VERSION 5.7 ;
BUSBITCHARS "[]" ;
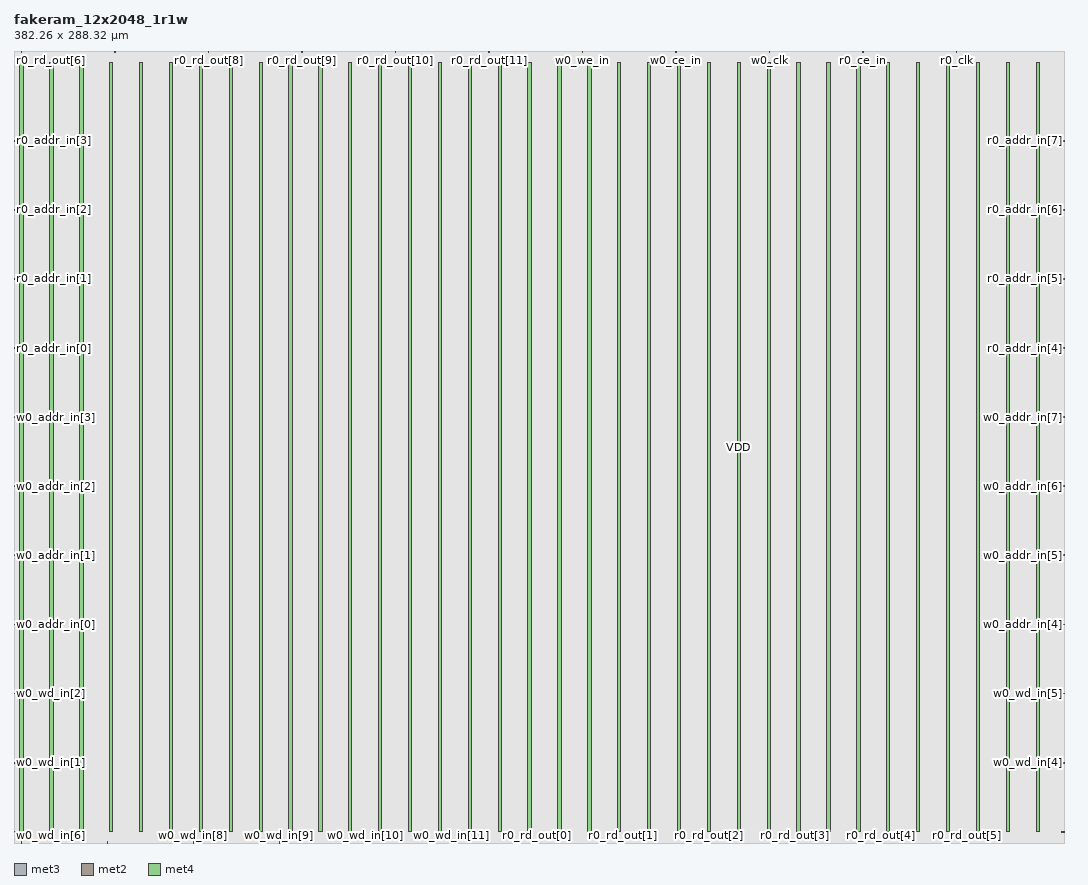
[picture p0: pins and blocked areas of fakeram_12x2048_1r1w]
MACRO fakeram_12x2048_1r1w
  FOREIGN fakeram_12x2048_1r1w 0 0 ;
  SYMMETRY X Y R90 ;
  SIZE 382.260 BY 288.320 ;
  CLASS BLOCK ;
  PIN w0_wd_in[0]
    DIRECTION INPUT ;
    USE SIGNAL ;
    SHAPE ABUTMENT ;
    PORT
      LAYER met3 ;
      RECT 0.000 3.930 0.900 4.230 ;
    END
  END w0_wd_in[0]
  PIN w0_wd_in[1]
    DIRECTION INPUT ;
    USE SIGNAL ;
    SHAPE ABUTMENT ;
    PORT
      LAYER met3 ;
      RECT 0.000 29.090 0.900 29.390 ;
    END
  END w0_wd_in[1]
  PIN w0_wd_in[2]
    DIRECTION INPUT ;
    USE SIGNAL ;
    SHAPE ABUTMENT ;
    PORT
      LAYER met3 ;
      RECT 0.000 54.250 0.900 54.550 ;
    END
  END w0_wd_in[2]
  PIN w0_wd_in[3]
    DIRECTION INPUT ;
    USE SIGNAL ;
    SHAPE ABUTMENT ;
    PORT
      LAYER met3 ;
      RECT 381.360 3.930 382.260 4.230 ;
    END
  END w0_wd_in[3]
  PIN w0_wd_in[4]
    DIRECTION INPUT ;
    USE SIGNAL ;
    SHAPE ABUTMENT ;
    PORT
      LAYER met3 ;
      RECT 381.360 29.090 382.260 29.390 ;
    END
  END w0_wd_in[4]
  PIN w0_wd_in[5]
    DIRECTION INPUT ;
    USE SIGNAL ;
    SHAPE ABUTMENT ;
    PORT
      LAYER met3 ;
      RECT 381.360 54.250 382.260 54.550 ;
    END
  END w0_wd_in[5]
  PIN w0_wd_in[6]
    DIRECTION OUTPUT ;
    USE SIGNAL ;
    SHAPE ABUTMENT ;
    PORT
      LAYER met2 ;
      RECT 2.690 0.000 2.830 0.420 ;
    END
  END w0_wd_in[6]
  PIN w0_wd_in[7]
    DIRECTION OUTPUT ;
    USE SIGNAL ;
    SHAPE ABUTMENT ;
    PORT
      LAYER met2 ;
      RECT 33.970 0.000 34.110 0.420 ;
    END
  END w0_wd_in[7]
  PIN w0_wd_in[8]
    DIRECTION OUTPUT ;
    USE SIGNAL ;
    SHAPE ABUTMENT ;
    PORT
      LAYER met2 ;
      RECT 65.250 0.000 65.390 0.420 ;
    END
  END w0_wd_in[8]
  PIN w0_wd_in[9]
    DIRECTION OUTPUT ;
    USE SIGNAL ;
    SHAPE ABUTMENT ;
    PORT
      LAYER met2 ;
      RECT 96.530 0.000 96.670 0.420 ;
    END
  END w0_wd_in[9]
  PIN w0_wd_in[10]
    DIRECTION OUTPUT ;
    USE SIGNAL ;
    SHAPE ABUTMENT ;
    PORT
      LAYER met2 ;
      RECT 127.810 0.000 127.950 0.420 ;
    END
  END w0_wd_in[10]
  PIN w0_wd_in[11]
    DIRECTION OUTPUT ;
    USE SIGNAL ;
    SHAPE ABUTMENT ;
    PORT
      LAYER met2 ;
      RECT 159.090 0.000 159.230 0.420 ;
    END
  END w0_wd_in[11]
  PIN r0_rd_out[0]
    DIRECTION OUTPUT ;
    USE SIGNAL ;
    SHAPE ABUTMENT ;
    PORT
      LAYER met2 ;
      RECT 190.370 0.000 190.510 0.420 ;
    END
  END r0_rd_out[0]
  PIN r0_rd_out[1]
    DIRECTION OUTPUT ;
    USE SIGNAL ;
    SHAPE ABUTMENT ;
    PORT
      LAYER met2 ;
      RECT 221.650 0.000 221.790 0.420 ;
    END
  END r0_rd_out[1]
  PIN r0_rd_out[2]
    DIRECTION OUTPUT ;
    USE SIGNAL ;
    SHAPE ABUTMENT ;
    PORT
      LAYER met2 ;
      RECT 252.930 0.000 253.070 0.420 ;
    END
  END r0_rd_out[2]
  PIN r0_rd_out[3]
    DIRECTION OUTPUT ;
    USE SIGNAL ;
    SHAPE ABUTMENT ;
    PORT
      LAYER met2 ;
      RECT 284.210 0.000 284.350 0.420 ;
    END
  END r0_rd_out[3]
  PIN r0_rd_out[4]
    DIRECTION OUTPUT ;
    USE SIGNAL ;
    SHAPE ABUTMENT ;
    PORT
      LAYER met2 ;
      RECT 315.490 0.000 315.630 0.420 ;
    END
  END r0_rd_out[4]
  PIN r0_rd_out[5]
    DIRECTION OUTPUT ;
    USE SIGNAL ;
    SHAPE ABUTMENT ;
    PORT
      LAYER met2 ;
      RECT 346.770 0.000 346.910 0.420 ;
    END
  END r0_rd_out[5]
  PIN r0_rd_out[6]
    DIRECTION OUTPUT ;
    USE SIGNAL ;
    SHAPE ABUTMENT ;
    PORT
      LAYER met2 ;
      RECT 2.690 287.900 2.830 288.320 ;
    END
  END r0_rd_out[6]
  PIN r0_rd_out[7]
    DIRECTION OUTPUT ;
    USE SIGNAL ;
    SHAPE ABUTMENT ;
    PORT
      LAYER met2 ;
      RECT 36.730 287.900 36.870 288.320 ;
    END
  END r0_rd_out[7]
  PIN r0_rd_out[8]
    DIRECTION OUTPUT ;
    USE SIGNAL ;
    SHAPE ABUTMENT ;
    PORT
      LAYER met2 ;
      RECT 70.770 287.900 70.910 288.320 ;
    END
  END r0_rd_out[8]
  PIN r0_rd_out[9]
    DIRECTION OUTPUT ;
    USE SIGNAL ;
    SHAPE ABUTMENT ;
    PORT
      LAYER met2 ;
      RECT 104.810 287.900 104.950 288.320 ;
    END
  END r0_rd_out[9]
  PIN r0_rd_out[10]
    DIRECTION OUTPUT ;
    USE SIGNAL ;
    SHAPE ABUTMENT ;
    PORT
      LAYER met2 ;
      RECT 138.850 287.900 138.990 288.320 ;
    END
  END r0_rd_out[10]
  PIN r0_rd_out[11]
    DIRECTION OUTPUT ;
    USE SIGNAL ;
    SHAPE ABUTMENT ;
    PORT
      LAYER met2 ;
      RECT 172.890 287.900 173.030 288.320 ;
    END
  END r0_rd_out[11]
  PIN w0_addr_in[0]
    DIRECTION INPUT ;
    USE SIGNAL ;
    SHAPE ABUTMENT ;
    PORT
      LAYER met3 ;
      RECT 0.000 79.410 0.900 79.710 ;
    END
  END w0_addr_in[0]
  PIN w0_addr_in[1]
    DIRECTION INPUT ;
    USE SIGNAL ;
    SHAPE ABUTMENT ;
    PORT
      LAYER met3 ;
      RECT 0.000 104.570 0.900 104.870 ;
    END
  END w0_addr_in[1]
  PIN w0_addr_in[2]
    DIRECTION INPUT ;
    USE SIGNAL ;
    SHAPE ABUTMENT ;
    PORT
      LAYER met3 ;
      RECT 0.000 129.730 0.900 130.030 ;
    END
  END w0_addr_in[2]
  PIN w0_addr_in[3]
    DIRECTION INPUT ;
    USE SIGNAL ;
    SHAPE ABUTMENT ;
    PORT
      LAYER met3 ;
      RECT 0.000 154.890 0.900 155.190 ;
    END
  END w0_addr_in[3]
  PIN w0_addr_in[4]
    DIRECTION INPUT ;
    USE SIGNAL ;
    SHAPE ABUTMENT ;
    PORT
      LAYER met3 ;
      RECT 381.360 79.410 382.260 79.710 ;
    END
  END w0_addr_in[4]
  PIN w0_addr_in[5]
    DIRECTION INPUT ;
    USE SIGNAL ;
    SHAPE ABUTMENT ;
    PORT
      LAYER met3 ;
      RECT 381.360 104.570 382.260 104.870 ;
    END
  END w0_addr_in[5]
  PIN w0_addr_in[6]
    DIRECTION INPUT ;
    USE SIGNAL ;
    SHAPE ABUTMENT ;
    PORT
      LAYER met3 ;
      RECT 381.360 129.730 382.260 130.030 ;
    END
  END w0_addr_in[6]
  PIN w0_addr_in[7]
    DIRECTION INPUT ;
    USE SIGNAL ;
    SHAPE ABUTMENT ;
    PORT
      LAYER met3 ;
      RECT 381.360 154.890 382.260 155.190 ;
    END
  END w0_addr_in[7]
  PIN r0_addr_in[0]
    DIRECTION INPUT ;
    USE SIGNAL ;
    SHAPE ABUTMENT ;
    PORT
      LAYER met3 ;
      RECT 0.000 180.050 0.900 180.350 ;
    END
  END r0_addr_in[0]
  PIN r0_addr_in[1]
    DIRECTION INPUT ;
    USE SIGNAL ;
    SHAPE ABUTMENT ;
    PORT
      LAYER met3 ;
      RECT 0.000 205.210 0.900 205.510 ;
    END
  END r0_addr_in[1]
  PIN r0_addr_in[2]
    DIRECTION INPUT ;
    USE SIGNAL ;
    SHAPE ABUTMENT ;
    PORT
      LAYER met3 ;
      RECT 0.000 230.370 0.900 230.670 ;
    END
  END r0_addr_in[2]
  PIN r0_addr_in[3]
    DIRECTION INPUT ;
    USE SIGNAL ;
    SHAPE ABUTMENT ;
    PORT
      LAYER met3 ;
      RECT 0.000 255.530 0.900 255.830 ;
    END
  END r0_addr_in[3]
  PIN r0_addr_in[4]
    DIRECTION INPUT ;
    USE SIGNAL ;
    SHAPE ABUTMENT ;
    PORT
      LAYER met3 ;
      RECT 381.360 180.050 382.260 180.350 ;
    END
  END r0_addr_in[4]
  PIN r0_addr_in[5]
    DIRECTION INPUT ;
    USE SIGNAL ;
    SHAPE ABUTMENT ;
    PORT
      LAYER met3 ;
      RECT 381.360 205.210 382.260 205.510 ;
    END
  END r0_addr_in[5]
  PIN r0_addr_in[6]
    DIRECTION INPUT ;
    USE SIGNAL ;
    SHAPE ABUTMENT ;
    PORT
      LAYER met3 ;
      RECT 381.360 230.370 382.260 230.670 ;
    END
  END r0_addr_in[6]
  PIN r0_addr_in[7]
    DIRECTION INPUT ;
    USE SIGNAL ;
    SHAPE ABUTMENT ;
    PORT
      LAYER met3 ;
      RECT 381.360 255.530 382.260 255.830 ;
    END
  END r0_addr_in[7]
  PIN w0_we_in
    DIRECTION INPUT ;
    USE SIGNAL ;
    SHAPE ABUTMENT ;
    PORT
      LAYER met2 ;
      RECT 206.930 287.900 207.070 288.320 ;
    END
  END w0_we_in
  PIN w0_ce_in
    DIRECTION INPUT ;
    USE SIGNAL ;
    SHAPE ABUTMENT ;
    PORT
      LAYER met2 ;
      RECT 240.970 287.900 241.110 288.320 ;
    END
  END w0_ce_in
  PIN w0_clk
    DIRECTION INPUT ;
    USE SIGNAL ;
    SHAPE ABUTMENT ;
    PORT
      LAYER met2 ;
      RECT 275.010 287.900 275.150 288.320 ;
    END
  END w0_clk
  PIN r0_ce_in
    DIRECTION INPUT ;
    USE SIGNAL ;
    SHAPE ABUTMENT ;
    PORT
      LAYER met2 ;
      RECT 309.050 287.900 309.190 288.320 ;
    END
  END r0_ce_in
  PIN r0_clk
    DIRECTION INPUT ;
    USE SIGNAL ;
    SHAPE ABUTMENT ;
    PORT
      LAYER met2 ;
      RECT 343.090 287.900 343.230 288.320 ;
    END
  END r0_clk
  PIN VSS
    DIRECTION INOUT ;
    USE GROUND ;
    PORT
      LAYER met4 ;
      RECT 2.160 4.080 3.360 284.240 ;
      RECT 13.040 4.080 14.240 284.240 ;
      RECT 23.920 4.080 25.120 284.240 ;
      RECT 34.800 4.080 36.000 284.240 ;
      RECT 45.680 4.080 46.880 284.240 ;
      RECT 56.560 4.080 57.760 284.240 ;
      RECT 67.440 4.080 68.640 284.240 ;
      RECT 78.320 4.080 79.520 284.240 ;
      RECT 89.200 4.080 90.400 284.240 ;
      RECT 100.080 4.080 101.280 284.240 ;
      RECT 110.960 4.080 112.160 284.240 ;
      RECT 121.840 4.080 123.040 284.240 ;
      RECT 132.720 4.080 133.920 284.240 ;
      RECT 143.600 4.080 144.800 284.240 ;
      RECT 154.480 4.080 155.680 284.240 ;
      RECT 165.360 4.080 166.560 284.240 ;
      RECT 176.240 4.080 177.440 284.240 ;
      RECT 187.120 4.080 188.320 284.240 ;
      RECT 198.000 4.080 199.200 284.240 ;
      RECT 208.880 4.080 210.080 284.240 ;
      RECT 219.760 4.080 220.960 284.240 ;
      RECT 230.640 4.080 231.840 284.240 ;
      RECT 241.520 4.080 242.720 284.240 ;
      RECT 252.400 4.080 253.600 284.240 ;
      RECT 263.280 4.080 264.480 284.240 ;
      RECT 274.160 4.080 275.360 284.240 ;
      RECT 285.040 4.080 286.240 284.240 ;
      RECT 295.920 4.080 297.120 284.240 ;
      RECT 306.800 4.080 308.000 284.240 ;
      RECT 317.680 4.080 318.880 284.240 ;
      RECT 328.560 4.080 329.760 284.240 ;
      RECT 339.440 4.080 340.640 284.240 ;
      RECT 350.320 4.080 351.520 284.240 ;
      RECT 361.200 4.080 362.400 284.240 ;
      RECT 372.080 4.080 373.280 284.240 ;
    END
  END VSS
  PIN VDD
    DIRECTION INOUT ;
    USE POWER ;
    PORT
      LAYER met4 ;
      RECT 2.160 4.080 3.360 284.240 ;
      RECT 13.040 4.080 14.240 284.240 ;
      RECT 23.920 4.080 25.120 284.240 ;
      RECT 34.800 4.080 36.000 284.240 ;
      RECT 45.680 4.080 46.880 284.240 ;
      RECT 56.560 4.080 57.760 284.240 ;
      RECT 67.440 4.080 68.640 284.240 ;
      RECT 78.320 4.080 79.520 284.240 ;
      RECT 89.200 4.080 90.400 284.240 ;
      RECT 100.080 4.080 101.280 284.240 ;
      RECT 110.960 4.080 112.160 284.240 ;
      RECT 121.840 4.080 123.040 284.240 ;
      RECT 132.720 4.080 133.920 284.240 ;
      RECT 143.600 4.080 144.800 284.240 ;
      RECT 154.480 4.080 155.680 284.240 ;
      RECT 165.360 4.080 166.560 284.240 ;
      RECT 176.240 4.080 177.440 284.240 ;
      RECT 187.120 4.080 188.320 284.240 ;
      RECT 198.000 4.080 199.200 284.240 ;
      RECT 208.880 4.080 210.080 284.240 ;
      RECT 219.760 4.080 220.960 284.240 ;
      RECT 230.640 4.080 231.840 284.240 ;
      RECT 241.520 4.080 242.720 284.240 ;
      RECT 252.400 4.080 253.600 284.240 ;
      RECT 263.280 4.080 264.480 284.240 ;
      RECT 274.160 4.080 275.360 284.240 ;
      RECT 285.040 4.080 286.240 284.240 ;
      RECT 295.920 4.080 297.120 284.240 ;
      RECT 306.800 4.080 308.000 284.240 ;
      RECT 317.680 4.080 318.880 284.240 ;
      RECT 328.560 4.080 329.760 284.240 ;
      RECT 339.440 4.080 340.640 284.240 ;
      RECT 350.320 4.080 351.520 284.240 ;
      RECT 361.200 4.080 362.400 284.240 ;
      RECT 372.080 4.080 373.280 284.240 ;
    END
  END VDD
  OBS
    LAYER met1 ;
    RECT 0 0 382.260 288.320 ;
    LAYER met2 ;
    RECT 0 0 382.260 288.320 ;
    LAYER met3 ;
    RECT 0 0 382.260 288.320 ;
    LAYER met4 ;
    RECT 0 0 382.260 288.320 ;
  END
END fakeram_12x2048_1r1w

END LIBRARY
